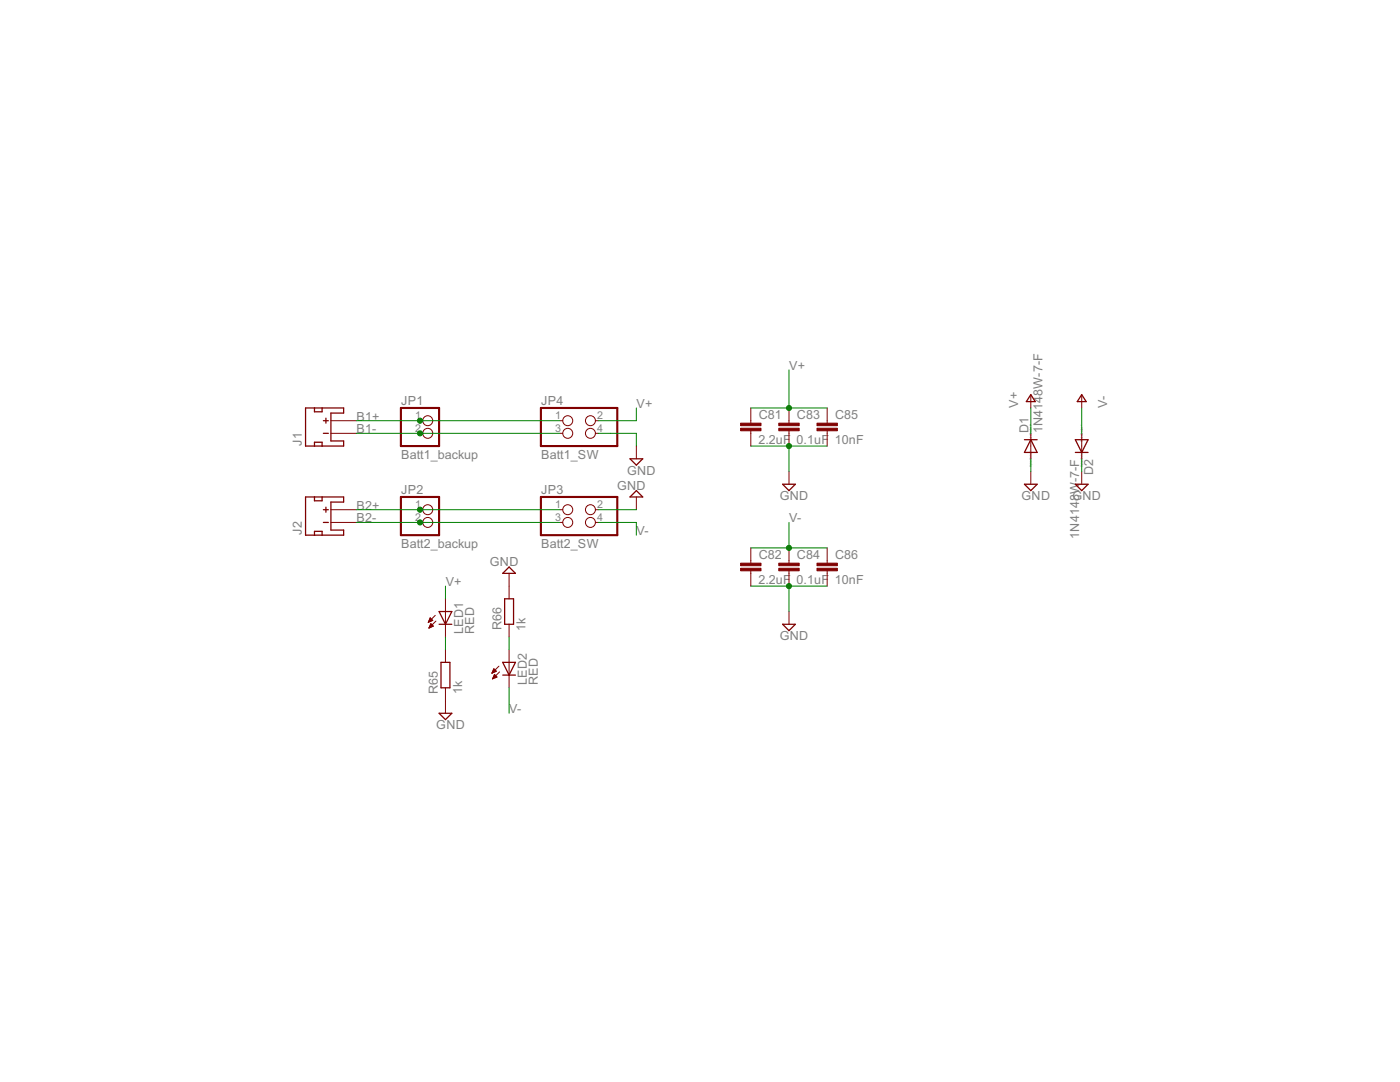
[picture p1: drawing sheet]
<svg xmlns="http://www.w3.org/2000/svg" width="279mm" height="216mm" viewBox="0 0 279 216" stroke-linecap="round" stroke-linejoin="round" font-family="sans-serif">
<defs><g id="words">
<g font-size="2.8" fill="#808080">
<text x="157.5" y="73.8">V+</text>
<text x="71.2" y="83.9">B1+</text>
<text x="80.1" y="80.8">JP1</text>
<text x="108" y="80.8">JP4</text>
<text x="127" y="81.4">V+</text>
<text x="151.4" y="83.6">C81</text>
<text x="159" y="83.6">C83</text>
<text x="166.7" y="83.6">C85</text>
<text x="203.2" y="81.4" transform="rotate(-90 203.2 81.4)">V+</text>
<text x="221" y="81.4" transform="rotate(-90 221 81.4)">V-</text>
<text x="60.2" y="89" transform="rotate(-90 60.2 89)">J1</text>
<text x="71.2" y="86.5">B1-</text>
<text x="151.4" y="88.6">2.2uF</text>
<text x="159" y="88.6">0.1uF</text>
<text x="166.6" y="88.6">10nF</text>
<text x="205.2" y="86.4" transform="rotate(-90 205.2 86.4)">D1</text>
<text x="208" y="86.5" transform="rotate(-90 208 86.5)">1N4148W-7-F</text>
<text x="80.1" y="91.6">Batt1_backup</text>
<text x="108" y="91.6">Batt1_SW</text>
<text x="125.1" y="94.7">GND</text>
<text x="218.1" y="94.8" transform="rotate(-90 218.1 94.8)">D2</text>
<text x="71.2" y="101.7">B2+</text>
<text x="80.1" y="98.5">JP2</text>
<text x="108" y="98.5">JP3</text>
<text x="123.1" y="97.8">GND</text>
<text x="155.6" y="99.8">GND</text>
<text x="203.9" y="99.8">GND</text>
<text x="214" y="99.8">GND</text>
<text x="215.3" y="96.2" transform="rotate(-90 215.3 96.2)">-7-F</text>
<text x="60.2" y="106.7" transform="rotate(-90 60.2 106.7)">J2</text>
<text x="71.2" y="104.2">B2-</text>
<text x="127" y="106.8">V-</text>
<text x="157.5" y="104.2">V-</text>
<text x="215.3" y="107.5" transform="rotate(-90 215.3 107.5)">1N4148W</text>
<text x="80.1" y="109.3">Batt2_backup</text>
<text x="97.7" y="113">GND</text>
<text x="108" y="109.3">Batt2_SW</text>
<text x="151.4" y="111.5">C82</text>
<text x="159" y="111.5">C84</text>
<text x="166.7" y="111.5">C86</text>
<text x="88.9" y="116.9">V+</text>
<text x="151.4" y="116.6">2.2uF</text>
<text x="159" y="116.6">0.1uF</text>
<text x="166.6" y="116.6">10nF</text>
<text x="100.1" y="125.8" transform="rotate(-90 100.1 125.8)">R66</text>
<text x="104.9" y="125.8" transform="rotate(-90 104.9 125.8)">1k</text>
<text x="92.5" y="126.5" transform="rotate(-90 92.5 126.5)">LED1</text>
<text x="94.6" y="126.5" transform="rotate(-90 94.6 126.5)">RED</text>
<text x="155.6" y="127.7">GND</text>
<text x="105.2" y="136.7" transform="rotate(-90 105.2 136.7)">LED2</text>
<text x="107.3" y="136.7" transform="rotate(-90 107.3 136.7)">RED</text>
<text x="87.4" y="138.5" transform="rotate(-90 87.4 138.5)">R65</text>
<text x="92.2" y="138.5" transform="rotate(-90 92.2 138.5)">1k</text>
<text x="101.6" y="142.3">V-</text>
<text x="87" y="145.5">GND</text>
</g>
<g font-size="2.4" fill="#808080">
<text x="82.8" y="83.6">1</text>
<text x="110.8" y="83.6">1</text>
<text x="119.2" y="83.6">2</text>
<text x="82.8" y="86.1">2</text>
<text x="110.8" y="86.1">3</text>
<text x="119.2" y="86.1">4</text>
<text x="82.8" y="101.4">1</text>
<text x="110.8" y="101.4">1</text>
<text x="119.2" y="101.4">2</text>
<text x="82.8" y="103.9">2</text>
<text x="110.8" y="103.9">3</text>
<text x="119.2" y="103.9">4</text>
</g>
<g font-size=".7" fill="#808080">
<text x="205.9" y="88.2" transform="rotate(-90 205.9 88.2)">SpiceOrder 2</text>
<text x="216.1" y="88.2" transform="rotate(-90 216.1 88.2)">SpiceOrder 1</text>
<text x="205.9" y="93.3" transform="rotate(-90 205.9 93.3)">SpiceOrder</text>
<text x="205.9" y="90.2" transform="rotate(-90 205.9 90.2)">1</text>
<text x="216.1" y="93.3" transform="rotate(-90 216.1 93.3)">SpiceOrder 2</text>
</g>
</g></defs>
<path d="M80 81.4h7.6v7.6h-7.6zM80 99.2h7.6v7.6h-7.6zM107.9 81.4h15.3v7.6h-15.3zM107.9 99.2h15.3v7.6h-15.3z" fill="none" stroke="#800000" stroke-width=".42"/>
<g fill="none" stroke="#800000" stroke-width=".2">
<path d="M205.7 78.9v2.5M215.9 78.9v2.5M66 83.9h5.1M66 86.5h5.1M83.8 83.9h.6M83.8 86.5h.6M111.8 83.9h.5M111.8 86.5h.5M118.8 83.9h.6M118.8 86.5h.6M127 89v2.5M127 99.2v2.5"/>
<path d="M149.8 81.4v3M149.8 86v3M157.5 81.4v3M157.5 86v3M157.5 94.1v2.5M165.1 81.4v3M165.1 86v3M205.7 86.5v5M205.7 94.1v2.5M215.9 86.5v5M215.9 94.1v2.5M66 101.7h5.1"/>
<path d="M66 104.2h5.1M83.8 101.7h.6M83.8 104.2h.6M88.9 119.5v7.6M101.6 114.4v5.1M111.8 101.7h.5M111.8 104.2h.5M118.8 101.7h.6M118.8 104.2h.6M149.8 109.3v3.1M149.8 113.9v3M157.5 109.3v3.1"/>
<path d="M157.5 113.9v3M165.1 109.3v3.1M165.1 113.9v3M85.5 124.1h.1M85.5 124h.3M85.6 123.9h.5M85.6 123.8h.8M85.6 125.2h.2M85.7 125.1h.4M85.7 123.7h.5M85.7 123.5h.4M85.7 125h.7"/>
<path d="M85.8 123.4h.2M85.8 124.9h.6M85.9 123.3l-.4 .9M85.9 123.3l.5 .5M85.9 123.3h.1M85.9 124.8h.4M85.9 124.6h.3M86 124.5h.1M86 124.4l.5 .5-.9 .4zM86.4 123.8l-.9 .4M86.9 122.8l-1.4 1.4M87 123.9l-1.4 1.4"/>
<path d="M88.9 129.6v2.6M88.9 137.2v5.1M98.2 134.3h.1M98.3 134.2h.3M98.3 134h.6M98.3 135.4h.3M98.4 133.9h.6M98.4 133.8h.5M98.4 135.2h.4M98.4 133.7h.4M98.4 135.1h.7M98.5 133.6h.2"/>
<path d="M98.5 135h.6M98.6 133.4l.5 .5-.9 .4zM98.6 134.9h.4M98.6 134.8h.2M98.7 134.6h.1M98.7 134.6l.5 .5-.9 .4zM99.6 132.9l-1.4 1.4M99.7 134.1l-1.4 1.4M101.6 124.6v2.5M101.6 129.6v7.6M157.5 122v2.6"/>
<circle cx="85.4" cy="86.5" r=".99"/>
<circle cx="85.4" cy="83.9" r=".99"/>
<circle cx="113.3" cy="86.5" r=".99"/>
<circle cx="113.3" cy="83.9" r=".99"/>
<circle cx="117.8" cy="86.5" r=".99"/>
<circle cx="117.8" cy="83.9" r=".99"/>
<circle cx="85.4" cy="104.2" r=".99"/>
<circle cx="85.4" cy="101.7" r=".99"/>
<circle cx="113.3" cy="104.2" r=".99"/>
<circle cx="113.3" cy="101.7" r=".99"/>
<circle cx="117.8" cy="104.2" r=".99"/>
<circle cx="117.8" cy="101.7" r=".99"/>
</g>
<g fill="none" stroke="#800000" stroke-width=".25">
<path d="M205.7 78.7l.9 1.4h-1.8zM215.9 78.7l.9 1.4h-1.8zM61 99.2h7.6v1h-2.6v5.6h2.6v1h-7.6zM61 81.4h7.6v1h-2.6v5.6h2.6v1h-7.6zM62.8 81.4v.8h1.5v-.8M62.8 89v-.8h1.5v.8M62.8 99.2v.7h1.5v-.7M64.5 83.9h1M64.5 86.5h1M65 83.4v1M125.7 91.5h2.6l-1.3 1.3zM127 97.9l1.3 1.3h-2.6z"/>
<path d="M156.2 96.6h2.5l-1.2 1.3zM204.4 96.6h2.6l-1.3 1.3zM204.4 87.7h2.6M205.7 87.7l1.3 2.6h-2.6zM214.6 96.6h2.5l-1.2 1.3zM214.6 87.7h2.5l-1.2 2.6zM214.6 90.3h2.5M62.8 106.8v-.8h1.5v.8M64.5 101.7h1M64.5 104.2h1M65 101.2v1M100.7 119.5h1.8v5.1h-1.8z"/>
<path d="M101.6 113.1l1.3 1.3h-2.6zM87.6 124.6h2.6M87.6 122h2.6l-1.3 2.6zM88 132.2h1.8v5h-1.8zM100.3 132.2h2.6l-1.3 2.5zM100.3 134.7h2.6M156.2 124.6h2.5l-1.2 1.2zM87.6 142.3h2.6l-1.3 1.3z"/>
</g>
<g fill="#800000" stroke="#800000" stroke-width=".2">
<path d="M155.4 85.4h4.1v.6h-4.1z"/>
<path d="M155.4 84.4h4.1v.5h-4.1z"/>
<path d="M155.4 113.4h4.1v.5h-4.1z"/>
<path d="M155.4 112.4h4.1v.5h-4.1z"/>
<path d="M163 85.4h4.1v.6h-4.1z"/>
<path d="M163 84.4h4.1v.5h-4.1z"/>
<path d="M147.8 85.4h4.1v.6h-4.1z"/>
<path d="M147.8 84.4h4.1v.5h-4.1z"/>
<path d="M147.8 113.4h4.1v.5h-4.1z"/>
<path d="M147.8 112.4h4.1v.5h-4.1z"/>
<path d="M163 113.4h4.1v.5h-4.1z"/>
<path d="M163 112.4h4.1v.5h-4.1z"/>
</g>
<g fill="none" stroke="#008000" stroke-width=".2">
<path d="M157.5 73.8v7.6M71.1 83.9h40.7M71.1 86.5h40.7M119.4 86.5h7.6v2.5M127 81.4v2.5h-7.6M149.8 81.4h15.3M149.8 89h15.3M157.5 89v5.1M205.7 81.4v5.1M205.7 91.5v2.6M215.9 81.4v5.1M215.9 91.5v2.6"/>
<path d="M71.1 104.2h40.7M71.1 101.7h40.7M88.9 116.9v2.6M119.4 104.2h7.6v2.6M119.4 101.7h7.6M149.8 109.3h15.3M149.8 116.9h15.3M157.5 104.2v5.1M157.5 116.9v5.1M88.9 127.1v2.5M101.6 127.1v2.5M101.6 137.2v5.1"/>
</g>
<g fill="#008000" stroke="#008000" stroke-width=".2">
<circle cx="157.5" cy="109.3" r=".51"/>
<circle cx="157.5" cy="81.4" r=".51"/>
<circle cx="157.5" cy="116.9" r=".51"/>
<circle cx="157.5" cy="89" r=".51"/>
<circle cx="83.8" cy="83.9" r=".51"/>
<circle cx="83.8" cy="86.5" r=".51"/>
<circle cx="83.8" cy="101.7" r=".51"/>
<circle cx="83.8" cy="104.2" r=".51"/>
</g>
<use href="#words"/>
</svg>
